VERSION 5.7 ;
  NOWIREEXTENSIONATPIN ON ;
  DIVIDERCHAR "/" ;
  BUSBITCHARS "[]" ;
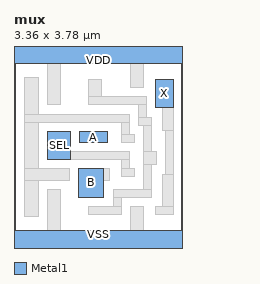
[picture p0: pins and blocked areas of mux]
MACRO mux
  CLASS CORE ;
  FOREIGN mux ;
  ORIGIN 0.000 0.000 ;
  SIZE 3.360 BY 3.780 ;
  SITE CoreSite ;
  SYMMETRY X Y ;
  PIN VSS
    DIRECTION INOUT ;
    USE GROUND ;
    PORT
      LAYER Metal1 ;
        RECT 0.000 -0.220 3.360 0.220 ;
    END
  END VSS
  PIN VDD
    DIRECTION INOUT ;
    USE POWER ;
    PORT
      LAYER Metal1 ;
        RECT 0.000 3.560 3.360 4.000 ;
    END
  END VDD
  PIN X
    DIRECTION OUTPUT ;
    ANTENNADIFFAREA 0.700400 ;
    PORT
      LAYER Metal1 ;
        RECT 2.820 2.670 3.170 3.230 ;
    END
  END X
  PIN A
    DIRECTION INPUT ;
    ANTENNAGATEAREA 0.221000 ;
    PORT
      LAYER Metal1 ;
        RECT 1.310 1.980 1.860 2.190 ;
    END
  END A
  PIN SEL
    DIRECTION INPUT ;
    ANTENNAGATEAREA 0.442000 ;
    PORT
      LAYER Metal1 ;
        RECT 0.670 1.640 1.130 2.190 ;
    END
  END SEL
  PIN B
    DIRECTION INPUT ;
    ANTENNAGATEAREA 0.221000 ;
    PORT
      LAYER Metal1 ;
        RECT 1.280 0.890 1.790 1.460 ;
    END
  END B
  OBS
      LAYER Metal1 ;
        RECT 0.210 2.530 0.490 3.280 ;
        RECT 0.670 2.730 0.930 3.560 ;
        RECT 1.490 2.890 1.750 3.230 ;
        RECT 2.310 3.070 2.570 3.560 ;
        RECT 1.490 2.730 2.640 2.890 ;
        RECT 0.210 2.370 2.295 2.530 ;
        RECT 0.210 1.460 0.490 2.370 ;
        RECT 2.135 2.140 2.295 2.370 ;
        RECT 2.475 2.480 2.640 2.730 ;
        RECT 2.475 2.320 2.740 2.480 ;
        RECT 2.135 1.980 2.400 2.140 ;
        RECT 2.580 1.810 2.740 2.320 ;
        RECT 2.960 2.220 3.170 2.670 ;
        RECT 1.130 1.640 2.300 1.800 ;
        RECT 2.140 1.460 2.300 1.640 ;
        RECT 2.580 1.550 2.830 1.810 ;
        RECT 0.210 1.230 1.100 1.460 ;
        RECT 1.790 1.230 1.890 1.460 ;
        RECT 2.140 1.300 2.400 1.460 ;
        RECT 0.210 0.500 0.490 1.230 ;
        RECT 2.580 1.050 2.740 1.550 ;
        RECT 3.010 1.340 3.170 2.220 ;
        RECT 0.670 0.220 0.930 1.050 ;
        RECT 1.970 0.890 2.740 1.050 ;
        RECT 1.970 0.710 2.130 0.890 ;
        RECT 2.960 0.710 3.170 1.340 ;
        RECT 1.490 0.550 2.130 0.710 ;
        RECT 2.310 0.220 2.570 0.710 ;
        RECT 2.820 0.550 3.170 0.710 ;
  END
END mux
END LIBRARY

